VERSION 5.7 ;
  NOWIREEXTENSIONATPIN ON ;
  DIVIDERCHAR "/" ;
  BUSBITCHARS "[]" ;
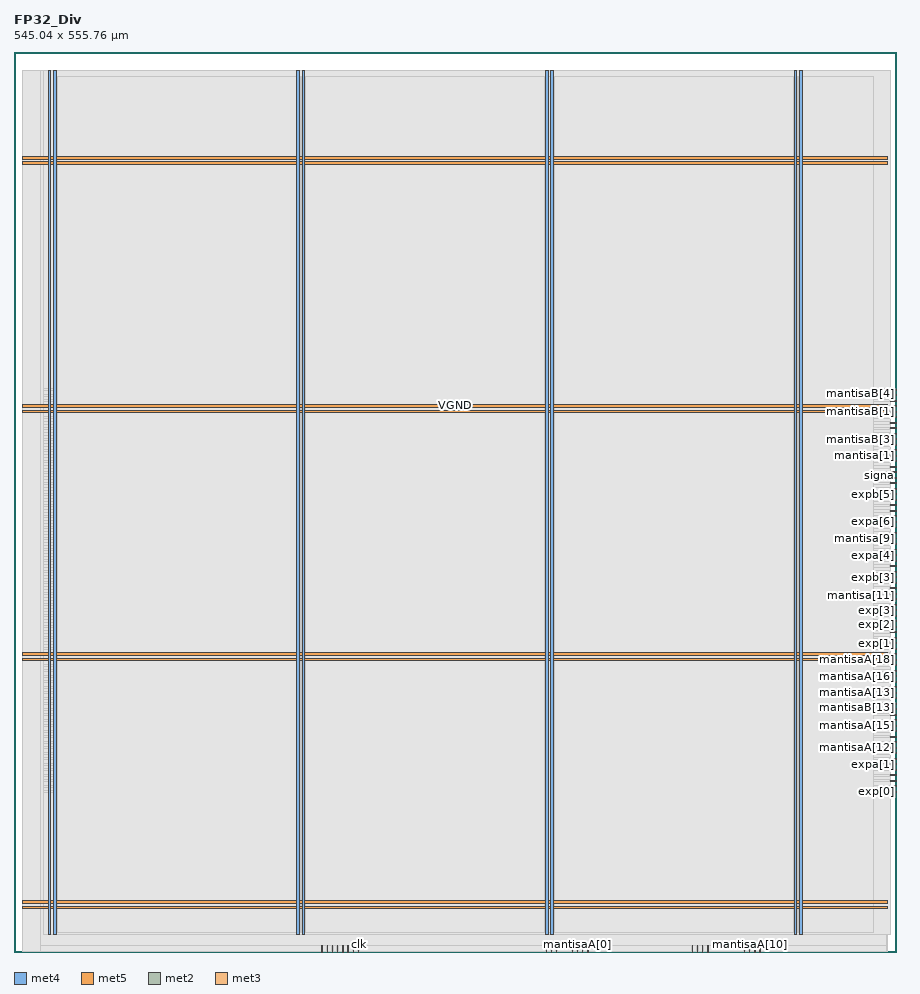
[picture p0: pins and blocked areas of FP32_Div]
MACRO FP32_Div
  CLASS BLOCK ;
  FOREIGN FP32_Div ;
  ORIGIN 0.000 0.000 ;
  SIZE 545.040 BY 555.760 ;
  PIN VGND
    DIRECTION INOUT ;
    USE GROUND ;
    PORT
      LAYER met4 ;
        RECT 24.340 10.640 25.940 544.240 ;
    END
    PORT
      LAYER met4 ;
        RECT 177.940 10.640 179.540 544.240 ;
    END
    PORT
      LAYER met4 ;
        RECT 331.540 10.640 333.140 544.240 ;
    END
    PORT
      LAYER met4 ;
        RECT 485.140 10.640 486.740 544.240 ;
    END
    PORT
      LAYER met5 ;
        RECT 5.280 30.030 539.360 31.630 ;
    END
    PORT
      LAYER met5 ;
        RECT 5.280 183.210 539.360 184.810 ;
    END
    PORT
      LAYER met5 ;
        RECT 5.280 336.390 539.360 337.990 ;
    END
    PORT
      LAYER met5 ;
        RECT 5.280 489.570 539.360 491.170 ;
    END
  END VGND
  PIN VPWR
    DIRECTION INOUT ;
    USE POWER ;
    PORT
      LAYER met4 ;
        RECT 21.040 10.640 22.640 544.240 ;
    END
    PORT
      LAYER met4 ;
        RECT 174.640 10.640 176.240 544.240 ;
    END
    PORT
      LAYER met4 ;
        RECT 328.240 10.640 329.840 544.240 ;
    END
    PORT
      LAYER met4 ;
        RECT 481.840 10.640 483.440 544.240 ;
    END
    PORT
      LAYER met5 ;
        RECT 5.280 26.730 539.360 28.330 ;
    END
    PORT
      LAYER met5 ;
        RECT 5.280 179.910 539.360 181.510 ;
    END
    PORT
      LAYER met5 ;
        RECT 5.280 333.090 539.360 334.690 ;
    END
    PORT
      LAYER met5 ;
        RECT 5.280 486.270 539.360 487.870 ;
    END
  END VPWR
  PIN clk
    DIRECTION INPUT ;
    USE SIGNAL ;
    ANTENNAGATEAREA 0.852000 ;
    PORT
      LAYER met2 ;
        RECT 212.610 0.000 212.890 4.000 ;
    END
  END clk
  PIN exp[0]
    DIRECTION OUTPUT ;
    USE SIGNAL ;
    ANTENNADIFFAREA 0.445500 ;
    PORT
      LAYER met3 ;
        RECT 541.040 98.640 545.040 99.240 ;
    END
  END exp[0]
  PIN exp[1]
    DIRECTION OUTPUT ;
    USE SIGNAL ;
    ANTENNADIFFAREA 0.445500 ;
    PORT
      LAYER met3 ;
        RECT 541.040 190.440 545.040 191.040 ;
    END
  END exp[1]
  PIN exp[2]
    DIRECTION OUTPUT ;
    USE SIGNAL ;
    ANTENNADIFFAREA 0.445500 ;
    PORT
      LAYER met3 ;
        RECT 541.040 197.240 545.040 197.840 ;
    END
  END exp[2]
  PIN exp[3]
    DIRECTION OUTPUT ;
    USE SIGNAL ;
    ANTENNADIFFAREA 0.445500 ;
    PORT
      LAYER met3 ;
        RECT 541.040 210.840 545.040 211.440 ;
    END
  END exp[3]
  PIN exp[4]
    DIRECTION OUTPUT ;
    USE SIGNAL ;
    ANTENNADIFFAREA 0.445500 ;
    PORT
      LAYER met3 ;
        RECT 541.040 346.840 545.040 347.440 ;
    END
  END exp[4]
  PIN exp[5]
    DIRECTION OUTPUT ;
    USE SIGNAL ;
    ANTENNADIFFAREA 0.445500 ;
    PORT
      LAYER met3 ;
        RECT 541.040 343.440 545.040 344.040 ;
    END
  END exp[5]
  PIN exp[6]
    DIRECTION OUTPUT ;
    USE SIGNAL ;
    ANTENNADIFFAREA 0.445500 ;
    PORT
      LAYER met3 ;
        RECT 541.040 309.440 545.040 310.040 ;
    END
  END exp[6]
  PIN exp[7]
    DIRECTION OUTPUT ;
    USE SIGNAL ;
    ANTENNADIFFAREA 0.445500 ;
    PORT
      LAYER met3 ;
        RECT 541.040 285.640 545.040 286.240 ;
    END
  END exp[7]
  PIN expa[0]
    DIRECTION INPUT ;
    USE SIGNAL ;
    ANTENNAGATEAREA 0.126000 ;
    PORT
      LAYER met3 ;
        RECT 541.040 204.040 545.040 204.640 ;
    END
  END expa[0]
  PIN expa[1]
    DIRECTION INPUT ;
    USE SIGNAL ;
    ANTENNAGATEAREA 0.126000 ;
    PORT
      LAYER met3 ;
        RECT 541.040 115.640 545.040 116.240 ;
    END
  END expa[1]
  PIN expa[2]
    DIRECTION INPUT ;
    USE SIGNAL ;
    ANTENNAGATEAREA 0.213000 ;
    PORT
      LAYER met3 ;
        RECT 541.040 105.440 545.040 106.040 ;
    END
  END expa[2]
  PIN expa[3]
    DIRECTION INPUT ;
    USE SIGNAL ;
    ANTENNAGATEAREA 0.213000 ;
    PORT
      LAYER met3 ;
        RECT 541.040 102.040 545.040 102.640 ;
    END
  END expa[3]
  PIN expa[4]
    DIRECTION INPUT ;
    USE SIGNAL ;
    ANTENNAGATEAREA 0.196500 ;
    PORT
      LAYER met3 ;
        RECT 541.040 244.840 545.040 245.440 ;
    END
  END expa[4]
  PIN expa[5]
    DIRECTION INPUT ;
    USE SIGNAL ;
    ANTENNAGATEAREA 0.213000 ;
    PORT
      LAYER met3 ;
        RECT 541.040 268.640 545.040 269.240 ;
    END
  END expa[5]
  PIN expa[6]
    DIRECTION INPUT ;
    USE SIGNAL ;
    ANTENNAGATEAREA 0.196500 ;
    PORT
      LAYER met3 ;
        RECT 541.040 265.240 545.040 265.840 ;
    END
  END expa[6]
  PIN expa[7]
    DIRECTION INPUT ;
    USE SIGNAL ;
    ANTENNAGATEAREA 0.196500 ;
    PORT
      LAYER met3 ;
        RECT 541.040 241.440 545.040 242.040 ;
    END
  END expa[7]
  PIN expb[0]
    DIRECTION INPUT ;
    USE SIGNAL ;
    ANTENNAGATEAREA 0.213000 ;
    PORT
      LAYER met3 ;
        RECT 541.040 119.040 545.040 119.640 ;
    END
  END expb[0]
  PIN expb[1]
    DIRECTION INPUT ;
    USE SIGNAL ;
    ANTENNAGATEAREA 0.126000 ;
    PORT
      LAYER met3 ;
        RECT 541.040 112.240 545.040 112.840 ;
    END
  END expb[1]
  PIN expb[2]
    DIRECTION INPUT ;
    USE SIGNAL ;
    ANTENNAGATEAREA 0.196500 ;
    PORT
      LAYER met3 ;
        RECT 541.040 217.640 545.040 218.240 ;
    END
  END expb[2]
  PIN expb[3]
    DIRECTION INPUT ;
    USE SIGNAL ;
    ANTENNAGATEAREA 0.126000 ;
    PORT
      LAYER met3 ;
        RECT 541.040 231.240 545.040 231.840 ;
    END
  END expb[3]
  PIN expb[4]
    DIRECTION INPUT ;
    USE SIGNAL ;
    ANTENNAGATEAREA 0.196500 ;
    PORT
      LAYER met3 ;
        RECT 541.040 234.640 545.040 235.240 ;
    END
  END expb[4]
  PIN expb[5]
    DIRECTION INPUT ;
    USE SIGNAL ;
    ANTENNAGATEAREA 0.213000 ;
    PORT
      LAYER met3 ;
        RECT 541.040 282.240 545.040 282.840 ;
    END
  END expb[5]
  PIN expb[6]
    DIRECTION INPUT ;
    USE SIGNAL ;
    ANTENNAGATEAREA 0.196500 ;
    PORT
      LAYER met3 ;
        RECT 541.040 302.640 545.040 303.240 ;
    END
  END expb[6]
  PIN expb[7]
    DIRECTION INPUT ;
    USE SIGNAL ;
    ANTENNAGATEAREA 0.126000 ;
    PORT
      LAYER met3 ;
        RECT 541.040 336.640 545.040 337.240 ;
    END
  END expb[7]
  PIN mantisaA[0]
    DIRECTION INPUT ;
    USE SIGNAL ;
    ANTENNAGATEAREA 0.196500 ;
    PORT
      LAYER met2 ;
        RECT 347.850 0.000 348.130 4.000 ;
    END
  END mantisaA[0]
  PIN mantisaA[10]
    DIRECTION INPUT ;
    USE SIGNAL ;
    ANTENNAGATEAREA 0.196500 ;
    PORT
      LAYER met2 ;
        RECT 454.110 0.000 454.390 4.000 ;
    END
  END mantisaA[10]
  PIN mantisaA[11]
    DIRECTION INPUT ;
    USE SIGNAL ;
    ANTENNAGATEAREA 0.196500 ;
    PORT
      LAYER met2 ;
        RECT 457.330 0.000 457.610 4.000 ;
    END
  END mantisaA[11]
  PIN mantisaA[12]
    DIRECTION INPUT ;
    USE SIGNAL ;
    ANTENNAGATEAREA 0.196500 ;
    PORT
      LAYER met3 ;
        RECT 541.040 125.840 545.040 126.440 ;
    END
  END mantisaA[12]
  PIN mantisaA[13]
    DIRECTION INPUT ;
    USE SIGNAL ;
    ANTENNAGATEAREA 0.196500 ;
    PORT
      LAYER met3 ;
        RECT 541.040 159.840 545.040 160.440 ;
    END
  END mantisaA[13]
  PIN mantisaA[14]
    DIRECTION INPUT ;
    USE SIGNAL ;
    ANTENNAGATEAREA 0.196500 ;
    PORT
      LAYER met3 ;
        RECT 541.040 156.440 545.040 157.040 ;
    END
  END mantisaA[14]
  PIN mantisaA[15]
    DIRECTION INPUT ;
    USE SIGNAL ;
    ANTENNAGATEAREA 0.196500 ;
    PORT
      LAYER met3 ;
        RECT 541.040 139.440 545.040 140.040 ;
    END
  END mantisaA[15]
  PIN mantisaA[16]
    DIRECTION INPUT ;
    USE SIGNAL ;
    ANTENNAGATEAREA 0.196500 ;
    PORT
      LAYER met3 ;
        RECT 541.040 170.040 545.040 170.640 ;
    END
  END mantisaA[16]
  PIN mantisaA[17]
    DIRECTION INPUT ;
    USE SIGNAL ;
    ANTENNAGATEAREA 0.196500 ;
    PORT
      LAYER met3 ;
        RECT 541.040 187.040 545.040 187.640 ;
    END
  END mantisaA[17]
  PIN mantisaA[18]
    DIRECTION INPUT ;
    USE SIGNAL ;
    ANTENNAGATEAREA 0.196500 ;
    PORT
      LAYER met3 ;
        RECT 541.040 180.240 545.040 180.840 ;
    END
  END mantisaA[18]
  PIN mantisaA[19]
    DIRECTION INPUT ;
    USE SIGNAL ;
    ANTENNAGATEAREA 0.196500 ;
    PORT
      LAYER met3 ;
        RECT 541.040 132.640 545.040 133.240 ;
    END
  END mantisaA[19]
  PIN mantisaA[1]
    DIRECTION INPUT ;
    USE SIGNAL ;
    ANTENNAGATEAREA 0.196500 ;
    PORT
      LAYER met2 ;
        RECT 351.070 0.000 351.350 4.000 ;
    END
  END mantisaA[1]
  PIN mantisaA[20]
    DIRECTION INPUT ;
    USE SIGNAL ;
    ANTENNAGATEAREA 0.196500 ;
    PORT
      LAYER met3 ;
        RECT 541.040 173.440 545.040 174.040 ;
    END
  END mantisaA[20]
  PIN mantisaA[21]
    DIRECTION INPUT ;
    USE SIGNAL ;
    ANTENNAGATEAREA 0.196500 ;
    PORT
      LAYER met3 ;
        RECT 541.040 183.640 545.040 184.240 ;
    END
  END mantisaA[21]
  PIN mantisaA[22]
    DIRECTION INPUT ;
    USE SIGNAL ;
    ANTENNAGATEAREA 0.196500 ;
    PORT
      LAYER met3 ;
        RECT 541.040 176.840 545.040 177.440 ;
    END
  END mantisaA[22]
  PIN mantisaA[2]
    DIRECTION INPUT ;
    USE SIGNAL ;
    ANTENNAGATEAREA 0.196500 ;
    PORT
      LAYER met2 ;
        RECT 344.630 0.000 344.910 4.000 ;
    END
  END mantisaA[2]
  PIN mantisaA[3]
    DIRECTION INPUT ;
    USE SIGNAL ;
    ANTENNAGATEAREA 0.196500 ;
    PORT
      LAYER met2 ;
        RECT 354.290 0.000 354.570 4.000 ;
    END
  END mantisaA[3]
  PIN mantisaA[4]
    DIRECTION INPUT ;
    USE SIGNAL ;
    ANTENNAGATEAREA 0.196500 ;
    PORT
      LAYER met2 ;
        RECT 421.910 0.000 422.190 4.000 ;
    END
  END mantisaA[4]
  PIN mantisaA[5]
    DIRECTION INPUT ;
    USE SIGNAL ;
    ANTENNAGATEAREA 0.196500 ;
    PORT
      LAYER met2 ;
        RECT 418.690 0.000 418.970 4.000 ;
    END
  END mantisaA[5]
  PIN mantisaA[6]
    DIRECTION INPUT ;
    USE SIGNAL ;
    ANTENNAGATEAREA 0.196500 ;
    PORT
      LAYER met2 ;
        RECT 425.130 0.000 425.410 4.000 ;
    END
  END mantisaA[6]
  PIN mantisaA[7]
    DIRECTION INPUT ;
    USE SIGNAL ;
    ANTENNAGATEAREA 0.196500 ;
    PORT
      LAYER met2 ;
        RECT 428.350 0.000 428.630 4.000 ;
    END
  END mantisaA[7]
  PIN mantisaA[8]
    DIRECTION INPUT ;
    USE SIGNAL ;
    ANTENNAGATEAREA 0.196500 ;
    PORT
      LAYER met2 ;
        RECT 450.890 0.000 451.170 4.000 ;
    END
  END mantisaA[8]
  PIN mantisaA[9]
    DIRECTION INPUT ;
    USE SIGNAL ;
    ANTENNAGATEAREA 0.196500 ;
    PORT
      LAYER met2 ;
        RECT 460.550 0.000 460.830 4.000 ;
    END
  END mantisaA[9]
  PIN mantisaB[0]
    DIRECTION INPUT ;
    USE SIGNAL ;
    ANTENNAGATEAREA 0.196500 ;
    PORT
      LAYER met3 ;
        RECT 541.040 312.840 545.040 313.440 ;
    END
  END mantisaB[0]
  PIN mantisaB[10]
    DIRECTION INPUT ;
    USE SIGNAL ;
    ANTENNAGATEAREA 0.196500 ;
    PORT
      LAYER met3 ;
        RECT 541.040 136.040 545.040 136.640 ;
    END
  END mantisaB[10]
  PIN mantisaB[11]
    DIRECTION INPUT ;
    USE SIGNAL ;
    ANTENNAGATEAREA 0.196500 ;
    PORT
      LAYER met3 ;
        RECT 541.040 163.240 545.040 163.840 ;
    END
  END mantisaB[11]
  PIN mantisaB[12]
    DIRECTION INPUT ;
    USE SIGNAL ;
    ANTENNAGATEAREA 0.196500 ;
    PORT
      LAYER met3 ;
        RECT 541.040 142.840 545.040 143.440 ;
    END
  END mantisaB[12]
  PIN mantisaB[13]
    DIRECTION INPUT ;
    USE SIGNAL ;
    ANTENNAGATEAREA 0.196500 ;
    PORT
      LAYER met3 ;
        RECT 541.040 146.240 545.040 146.840 ;
    END
  END mantisaB[13]
  PIN mantisaB[14]
    DIRECTION INPUT ;
    USE SIGNAL ;
    ANTENNAGATEAREA 0.196500 ;
    PORT
      LAYER met3 ;
        RECT 541.040 153.040 545.040 153.640 ;
    END
  END mantisaB[14]
  PIN mantisaB[15]
    DIRECTION INPUT ;
    USE SIGNAL ;
    ANTENNAGATEAREA 0.196500 ;
    PORT
      LAYER met3 ;
        RECT 541.040 149.640 545.040 150.240 ;
    END
  END mantisaB[15]
  PIN mantisaB[16]
    DIRECTION INPUT ;
    USE SIGNAL ;
    ANTENNAGATEAREA 0.196500 ;
    PORT
      LAYER met2 ;
        RECT 190.070 0.000 190.350 4.000 ;
    END
  END mantisaB[16]
  PIN mantisaB[17]
    DIRECTION INPUT ;
    USE SIGNAL ;
    ANTENNAGATEAREA 0.196500 ;
    PORT
      LAYER met2 ;
        RECT 196.510 0.000 196.790 4.000 ;
    END
  END mantisaB[17]
  PIN mantisaB[18]
    DIRECTION INPUT ;
    USE SIGNAL ;
    ANTENNAGATEAREA 0.196500 ;
    PORT
      LAYER met2 ;
        RECT 193.290 0.000 193.570 4.000 ;
    END
  END mantisaB[18]
  PIN mantisaB[19]
    DIRECTION INPUT ;
    USE SIGNAL ;
    ANTENNAGATEAREA 0.196500 ;
    PORT
      LAYER met2 ;
        RECT 199.730 0.000 200.010 4.000 ;
    END
  END mantisaB[19]
  PIN mantisaB[1]
    DIRECTION INPUT ;
    USE SIGNAL ;
    ANTENNAGATEAREA 0.196500 ;
    PORT
      LAYER met3 ;
        RECT 541.040 333.240 545.040 333.840 ;
    END
  END mantisaB[1]
  PIN mantisaB[20]
    DIRECTION INPUT ;
    USE SIGNAL ;
    ANTENNAGATEAREA 0.196500 ;
    PORT
      LAYER met2 ;
        RECT 202.950 0.000 203.230 4.000 ;
    END
  END mantisaB[20]
  PIN mantisaB[21]
    DIRECTION INPUT ;
    USE SIGNAL ;
    ANTENNAGATEAREA 0.196500 ;
    PORT
      LAYER met2 ;
        RECT 206.170 0.000 206.450 4.000 ;
    END
  END mantisaB[21]
  PIN mantisaB[22]
    DIRECTION INPUT ;
    USE SIGNAL ;
    ANTENNAGATEAREA 0.196500 ;
    PORT
      LAYER met2 ;
        RECT 209.390 0.000 209.670 4.000 ;
    END
  END mantisaB[22]
  PIN mantisaB[2]
    DIRECTION INPUT ;
    USE SIGNAL ;
    ANTENNAGATEAREA 0.196500 ;
    PORT
      LAYER met3 ;
        RECT 541.040 275.440 545.040 276.040 ;
    END
  END mantisaB[2]
  PIN mantisaB[3]
    DIRECTION INPUT ;
    USE SIGNAL ;
    ANTENNAGATEAREA 0.196500 ;
    PORT
      LAYER met3 ;
        RECT 541.040 316.240 545.040 316.840 ;
    END
  END mantisaB[3]
  PIN mantisaB[4]
    DIRECTION INPUT ;
    USE SIGNAL ;
    ANTENNAGATEAREA 0.196500 ;
    PORT
      LAYER met3 ;
        RECT 541.040 340.040 545.040 340.640 ;
    END
  END mantisaB[4]
  PIN mantisaB[5]
    DIRECTION INPUT ;
    USE SIGNAL ;
    ANTENNAGATEAREA 0.196500 ;
    PORT
      LAYER met3 ;
        RECT 541.040 258.440 545.040 259.040 ;
    END
  END mantisaB[5]
  PIN mantisaB[6]
    DIRECTION INPUT ;
    USE SIGNAL ;
    ANTENNAGATEAREA 0.196500 ;
    PORT
      LAYER met3 ;
        RECT 541.040 248.240 545.040 248.840 ;
    END
  END mantisaB[6]
  PIN mantisaB[7]
    DIRECTION INPUT ;
    USE SIGNAL ;
    ANTENNAGATEAREA 0.196500 ;
    PORT
      LAYER met3 ;
        RECT 541.040 323.040 545.040 323.640 ;
    END
  END mantisaB[7]
  PIN mantisaB[8]
    DIRECTION INPUT ;
    USE SIGNAL ;
    ANTENNAGATEAREA 0.196500 ;
    PORT
      LAYER met3 ;
        RECT 541.040 129.240 545.040 129.840 ;
    END
  END mantisaB[8]
  PIN mantisaB[9]
    DIRECTION INPUT ;
    USE SIGNAL ;
    ANTENNAGATEAREA 0.196500 ;
    PORT
      LAYER met3 ;
        RECT 541.040 166.640 545.040 167.240 ;
    END
  END mantisaB[9]
  PIN mantisa[0]
    DIRECTION OUTPUT ;
    USE SIGNAL ;
    ANTENNADIFFAREA 0.445500 ;
    PORT
      LAYER met3 ;
        RECT 541.040 326.440 545.040 327.040 ;
    END
  END mantisa[0]
  PIN mantisa[10]
    DIRECTION OUTPUT ;
    USE SIGNAL ;
    ANTENNADIFFAREA 0.445500 ;
    PORT
      LAYER met3 ;
        RECT 541.040 251.640 545.040 252.240 ;
    END
  END mantisa[10]
  PIN mantisa[11]
    DIRECTION OUTPUT ;
    USE SIGNAL ;
    ANTENNADIFFAREA 0.445500 ;
    PORT
      LAYER met3 ;
        RECT 541.040 224.440 545.040 225.040 ;
    END
  END mantisa[11]
  PIN mantisa[12]
    DIRECTION OUTPUT ;
    USE SIGNAL ;
    ANTENNADIFFAREA 0.445500 ;
    PORT
      LAYER met3 ;
        RECT 541.040 221.040 545.040 221.640 ;
    END
  END mantisa[12]
  PIN mantisa[13]
    DIRECTION OUTPUT ;
    USE SIGNAL ;
    ANTENNADIFFAREA 0.445500 ;
    PORT
      LAYER met2 ;
        RECT 328.530 0.000 328.810 4.000 ;
    END
  END mantisa[13]
  PIN mantisa[14]
    DIRECTION OUTPUT ;
    USE SIGNAL ;
    ANTENNADIFFAREA 0.445500 ;
    PORT
      LAYER met3 ;
        RECT 541.040 214.240 545.040 214.840 ;
    END
  END mantisa[14]
  PIN mantisa[15]
    DIRECTION OUTPUT ;
    USE SIGNAL ;
    ANTENNADIFFAREA 0.445500 ;
    PORT
      LAYER met3 ;
        RECT 541.040 261.840 545.040 262.440 ;
    END
  END mantisa[15]
  PIN mantisa[16]
    DIRECTION OUTPUT ;
    USE SIGNAL ;
    ANTENNADIFFAREA 0.445500 ;
    PORT
      LAYER met3 ;
        RECT 541.040 295.840 545.040 296.440 ;
    END
  END mantisa[16]
  PIN mantisa[17]
    DIRECTION OUTPUT ;
    USE SIGNAL ;
    ANTENNADIFFAREA 0.445500 ;
    PORT
      LAYER met3 ;
        RECT 541.040 278.840 545.040 279.440 ;
    END
  END mantisa[17]
  PIN mantisa[18]
    DIRECTION OUTPUT ;
    USE SIGNAL ;
    ANTENNADIFFAREA 0.445500 ;
    PORT
      LAYER met3 ;
        RECT 541.040 238.040 545.040 238.640 ;
    END
  END mantisa[18]
  PIN mantisa[19]
    DIRECTION OUTPUT ;
    USE SIGNAL ;
    ANTENNADIFFAREA 0.445500 ;
    PORT
      LAYER met3 ;
        RECT 541.040 227.840 545.040 228.440 ;
    END
  END mantisa[19]
  PIN mantisa[1]
    DIRECTION OUTPUT ;
    USE SIGNAL ;
    ANTENNADIFFAREA 0.445500 ;
    PORT
      LAYER met3 ;
        RECT 541.040 306.040 545.040 306.640 ;
    END
  END mantisa[1]
  PIN mantisa[20]
    DIRECTION OUTPUT ;
    USE SIGNAL ;
    ANTENNADIFFAREA 0.445500 ;
    PORT
      LAYER met3 ;
        RECT 541.040 193.840 545.040 194.440 ;
    END
  END mantisa[20]
  PIN mantisa[21]
    DIRECTION OUTPUT ;
    USE SIGNAL ;
    ANTENNADIFFAREA 0.445500 ;
    PORT
      LAYER met3 ;
        RECT 541.040 207.440 545.040 208.040 ;
    END
  END mantisa[21]
  PIN mantisa[22]
    DIRECTION OUTPUT ;
    USE SIGNAL ;
    ANTENNADIFFAREA 0.445500 ;
    PORT
      LAYER met3 ;
        RECT 541.040 108.840 545.040 109.440 ;
    END
  END mantisa[22]
  PIN mantisa[2]
    DIRECTION OUTPUT ;
    USE SIGNAL ;
    ANTENNADIFFAREA 0.445500 ;
    PORT
      LAYER met3 ;
        RECT 541.040 272.040 545.040 272.640 ;
    END
  END mantisa[2]
  PIN mantisa[3]
    DIRECTION OUTPUT ;
    USE SIGNAL ;
    ANTENNADIFFAREA 0.445500 ;
    PORT
      LAYER met2 ;
        RECT 331.750 0.000 332.030 4.000 ;
    END
  END mantisa[3]
  PIN mantisa[4]
    DIRECTION OUTPUT ;
    USE SIGNAL ;
    ANTENNADIFFAREA 0.445500 ;
    PORT
      LAYER met3 ;
        RECT 541.040 122.440 545.040 123.040 ;
    END
  END mantisa[4]
  PIN mantisa[5]
    DIRECTION OUTPUT ;
    USE SIGNAL ;
    ANTENNADIFFAREA 0.445500 ;
    PORT
      LAYER met3 ;
        RECT 541.040 200.640 545.040 201.240 ;
    END
  END mantisa[5]
  PIN mantisa[6]
    DIRECTION OUTPUT ;
    USE SIGNAL ;
    ANTENNADIFFAREA 0.445500 ;
    PORT
      LAYER met2 ;
        RECT 334.970 0.000 335.250 4.000 ;
    END
  END mantisa[6]
  PIN mantisa[7]
    DIRECTION OUTPUT ;
    USE SIGNAL ;
    ANTENNADIFFAREA 0.445500 ;
    PORT
      LAYER met3 ;
        RECT 541.040 319.640 545.040 320.240 ;
    END
  END mantisa[7]
  PIN mantisa[8]
    DIRECTION OUTPUT ;
    USE SIGNAL ;
    ANTENNADIFFAREA 0.445500 ;
    PORT
      LAYER met3 ;
        RECT 541.040 329.840 545.040 330.440 ;
    END
  END mantisa[8]
  PIN mantisa[9]
    DIRECTION OUTPUT ;
    USE SIGNAL ;
    ANTENNADIFFAREA 0.445500 ;
    PORT
      LAYER met3 ;
        RECT 541.040 255.040 545.040 255.640 ;
    END
  END mantisa[9]
  PIN sign
    DIRECTION OUTPUT ;
    USE SIGNAL ;
    ANTENNADIFFAREA 0.445500 ;
    PORT
      LAYER met3 ;
        RECT 541.040 292.440 545.040 293.040 ;
    END
  END sign
  PIN signa
    DIRECTION INPUT ;
    USE SIGNAL ;
    ANTENNAGATEAREA 0.196500 ;
    PORT
      LAYER met3 ;
        RECT 541.040 289.040 545.040 289.640 ;
    END
  END signa
  PIN signb
    DIRECTION INPUT ;
    USE SIGNAL ;
    ANTENNAGATEAREA 0.196500 ;
    PORT
      LAYER met3 ;
        RECT 541.040 299.240 545.040 299.840 ;
    END
  END signb
  OBS
      LAYER nwell ;
        RECT 5.330 10.795 539.310 544.085 ;
      LAYER li1 ;
        RECT 5.520 10.795 539.120 544.085 ;
      LAYER met1 ;
        RECT 5.520 0.380 539.420 544.240 ;
      LAYER met2 ;
        RECT 16.200 4.280 539.020 544.185 ;
        RECT 16.200 0.350 189.790 4.280 ;
        RECT 190.630 0.350 193.010 4.280 ;
        RECT 193.850 0.350 196.230 4.280 ;
        RECT 197.070 0.350 199.450 4.280 ;
        RECT 200.290 0.350 202.670 4.280 ;
        RECT 203.510 0.350 205.890 4.280 ;
        RECT 206.730 0.350 209.110 4.280 ;
        RECT 209.950 0.350 212.330 4.280 ;
        RECT 213.170 0.350 328.250 4.280 ;
        RECT 329.090 0.350 331.470 4.280 ;
        RECT 332.310 0.350 334.690 4.280 ;
        RECT 335.530 0.350 344.350 4.280 ;
        RECT 345.190 0.350 347.570 4.280 ;
        RECT 348.410 0.350 350.790 4.280 ;
        RECT 351.630 0.350 354.010 4.280 ;
        RECT 354.850 0.350 418.410 4.280 ;
        RECT 419.250 0.350 421.630 4.280 ;
        RECT 422.470 0.350 424.850 4.280 ;
        RECT 425.690 0.350 428.070 4.280 ;
        RECT 428.910 0.350 450.610 4.280 ;
        RECT 451.450 0.350 453.830 4.280 ;
        RECT 454.670 0.350 457.050 4.280 ;
        RECT 457.890 0.350 460.270 4.280 ;
        RECT 461.110 0.350 539.020 4.280 ;
      LAYER met3 ;
        RECT 18.465 347.840 541.040 544.165 ;
        RECT 18.465 346.440 540.640 347.840 ;
        RECT 18.465 344.440 541.040 346.440 ;
        RECT 18.465 343.040 540.640 344.440 ;
        RECT 18.465 341.040 541.040 343.040 ;
        RECT 18.465 339.640 540.640 341.040 ;
        RECT 18.465 337.640 541.040 339.640 ;
        RECT 18.465 336.240 540.640 337.640 ;
        RECT 18.465 334.240 541.040 336.240 ;
        RECT 18.465 332.840 540.640 334.240 ;
        RECT 18.465 330.840 541.040 332.840 ;
        RECT 18.465 329.440 540.640 330.840 ;
        RECT 18.465 327.440 541.040 329.440 ;
        RECT 18.465 326.040 540.640 327.440 ;
        RECT 18.465 324.040 541.040 326.040 ;
        RECT 18.465 322.640 540.640 324.040 ;
        RECT 18.465 320.640 541.040 322.640 ;
        RECT 18.465 319.240 540.640 320.640 ;
        RECT 18.465 317.240 541.040 319.240 ;
        RECT 18.465 315.840 540.640 317.240 ;
        RECT 18.465 313.840 541.040 315.840 ;
        RECT 18.465 312.440 540.640 313.840 ;
        RECT 18.465 310.440 541.040 312.440 ;
        RECT 18.465 309.040 540.640 310.440 ;
        RECT 18.465 307.040 541.040 309.040 ;
        RECT 18.465 305.640 540.640 307.040 ;
        RECT 18.465 303.640 541.040 305.640 ;
        RECT 18.465 302.240 540.640 303.640 ;
        RECT 18.465 300.240 541.040 302.240 ;
        RECT 18.465 298.840 540.640 300.240 ;
        RECT 18.465 296.840 541.040 298.840 ;
        RECT 18.465 295.440 540.640 296.840 ;
        RECT 18.465 293.440 541.040 295.440 ;
        RECT 18.465 292.040 540.640 293.440 ;
        RECT 18.465 290.040 541.040 292.040 ;
        RECT 18.465 288.640 540.640 290.040 ;
        RECT 18.465 286.640 541.040 288.640 ;
        RECT 18.465 285.240 540.640 286.640 ;
        RECT 18.465 283.240 541.040 285.240 ;
        RECT 18.465 281.840 540.640 283.240 ;
        RECT 18.465 279.840 541.040 281.840 ;
        RECT 18.465 278.440 540.640 279.840 ;
        RECT 18.465 276.440 541.040 278.440 ;
        RECT 18.465 275.040 540.640 276.440 ;
        RECT 18.465 273.040 541.040 275.040 ;
        RECT 18.465 271.640 540.640 273.040 ;
        RECT 18.465 269.640 541.040 271.640 ;
        RECT 18.465 268.240 540.640 269.640 ;
        RECT 18.465 266.240 541.040 268.240 ;
        RECT 18.465 264.840 540.640 266.240 ;
        RECT 18.465 262.840 541.040 264.840 ;
        RECT 18.465 261.440 540.640 262.840 ;
        RECT 18.465 259.440 541.040 261.440 ;
        RECT 18.465 258.040 540.640 259.440 ;
        RECT 18.465 256.040 541.040 258.040 ;
        RECT 18.465 254.640 540.640 256.040 ;
        RECT 18.465 252.640 541.040 254.640 ;
        RECT 18.465 251.240 540.640 252.640 ;
        RECT 18.465 249.240 541.040 251.240 ;
        RECT 18.465 247.840 540.640 249.240 ;
        RECT 18.465 245.840 541.040 247.840 ;
        RECT 18.465 244.440 540.640 245.840 ;
        RECT 18.465 242.440 541.040 244.440 ;
        RECT 18.465 241.040 540.640 242.440 ;
        RECT 18.465 239.040 541.040 241.040 ;
        RECT 18.465 237.640 540.640 239.040 ;
        RECT 18.465 235.640 541.040 237.640 ;
        RECT 18.465 234.240 540.640 235.640 ;
        RECT 18.465 232.240 541.040 234.240 ;
        RECT 18.465 230.840 540.640 232.240 ;
        RECT 18.465 228.840 541.040 230.840 ;
        RECT 18.465 227.440 540.640 228.840 ;
        RECT 18.465 225.440 541.040 227.440 ;
        RECT 18.465 224.040 540.640 225.440 ;
        RECT 18.465 222.040 541.040 224.040 ;
        RECT 18.465 220.640 540.640 222.040 ;
        RECT 18.465 218.640 541.040 220.640 ;
        RECT 18.465 217.240 540.640 218.640 ;
        RECT 18.465 215.240 541.040 217.240 ;
        RECT 18.465 213.840 540.640 215.240 ;
        RECT 18.465 211.840 541.040 213.840 ;
        RECT 18.465 210.440 540.640 211.840 ;
        RECT 18.465 208.440 541.040 210.440 ;
        RECT 18.465 207.040 540.640 208.440 ;
        RECT 18.465 205.040 541.040 207.040 ;
        RECT 18.465 203.640 540.640 205.040 ;
        RECT 18.465 201.640 541.040 203.640 ;
        RECT 18.465 200.240 540.640 201.640 ;
        RECT 18.465 198.240 541.040 200.240 ;
        RECT 18.465 196.840 540.640 198.240 ;
        RECT 18.465 194.840 541.040 196.840 ;
        RECT 18.465 193.440 540.640 194.840 ;
        RECT 18.465 191.440 541.040 193.440 ;
        RECT 18.465 190.040 540.640 191.440 ;
        RECT 18.465 188.040 541.040 190.040 ;
        RECT 18.465 186.640 540.640 188.040 ;
        RECT 18.465 184.640 541.040 186.640 ;
        RECT 18.465 183.240 540.640 184.640 ;
        RECT 18.465 181.240 541.040 183.240 ;
        RECT 18.465 179.840 540.640 181.240 ;
        RECT 18.465 177.840 541.040 179.840 ;
        RECT 18.465 176.440 540.640 177.840 ;
        RECT 18.465 174.440 541.040 176.440 ;
        RECT 18.465 173.040 540.640 174.440 ;
        RECT 18.465 171.040 541.040 173.040 ;
        RECT 18.465 169.640 540.640 171.040 ;
        RECT 18.465 167.640 541.040 169.640 ;
        RECT 18.465 166.240 540.640 167.640 ;
        RECT 18.465 164.240 541.040 166.240 ;
        RECT 18.465 162.840 540.640 164.240 ;
        RECT 18.465 160.840 541.040 162.840 ;
        RECT 18.465 159.440 540.640 160.840 ;
        RECT 18.465 157.440 541.040 159.440 ;
        RECT 18.465 156.040 540.640 157.440 ;
        RECT 18.465 154.040 541.040 156.040 ;
        RECT 18.465 152.640 540.640 154.040 ;
        RECT 18.465 150.640 541.040 152.640 ;
        RECT 18.465 149.240 540.640 150.640 ;
        RECT 18.465 147.240 541.040 149.240 ;
        RECT 18.465 145.840 540.640 147.240 ;
        RECT 18.465 143.840 541.040 145.840 ;
        RECT 18.465 142.440 540.640 143.840 ;
        RECT 18.465 140.440 541.040 142.440 ;
        RECT 18.465 139.040 540.640 140.440 ;
        RECT 18.465 137.040 541.040 139.040 ;
        RECT 18.465 135.640 540.640 137.040 ;
        RECT 18.465 133.640 541.040 135.640 ;
        RECT 18.465 132.240 540.640 133.640 ;
        RECT 18.465 130.240 541.040 132.240 ;
        RECT 18.465 128.840 540.640 130.240 ;
        RECT 18.465 126.840 541.040 128.840 ;
        RECT 18.465 125.440 540.640 126.840 ;
        RECT 18.465 123.440 541.040 125.440 ;
        RECT 18.465 122.040 540.640 123.440 ;
        RECT 18.465 120.040 541.040 122.040 ;
        RECT 18.465 118.640 540.640 120.040 ;
        RECT 18.465 116.640 541.040 118.640 ;
        RECT 18.465 115.240 540.640 116.640 ;
        RECT 18.465 113.240 541.040 115.240 ;
        RECT 18.465 111.840 540.640 113.240 ;
        RECT 18.465 109.840 541.040 111.840 ;
        RECT 18.465 108.440 540.640 109.840 ;
        RECT 18.465 106.440 541.040 108.440 ;
        RECT 18.465 105.040 540.640 106.440 ;
        RECT 18.465 103.040 541.040 105.040 ;
        RECT 18.465 101.640 540.640 103.040 ;
        RECT 18.465 99.640 541.040 101.640 ;
        RECT 18.465 98.240 540.640 99.640 ;
        RECT 18.465 10.715 541.040 98.240 ;
      LAYER met4 ;
        RECT 26.975 11.735 174.240 540.425 ;
        RECT 176.640 11.735 177.540 540.425 ;
        RECT 179.940 11.735 327.840 540.425 ;
        RECT 330.240 11.735 331.140 540.425 ;
        RECT 333.540 11.735 481.440 540.425 ;
        RECT 483.840 11.735 484.740 540.425 ;
        RECT 487.140 11.735 530.545 540.425 ;
  END
END FP32_Div
END LIBRARY

